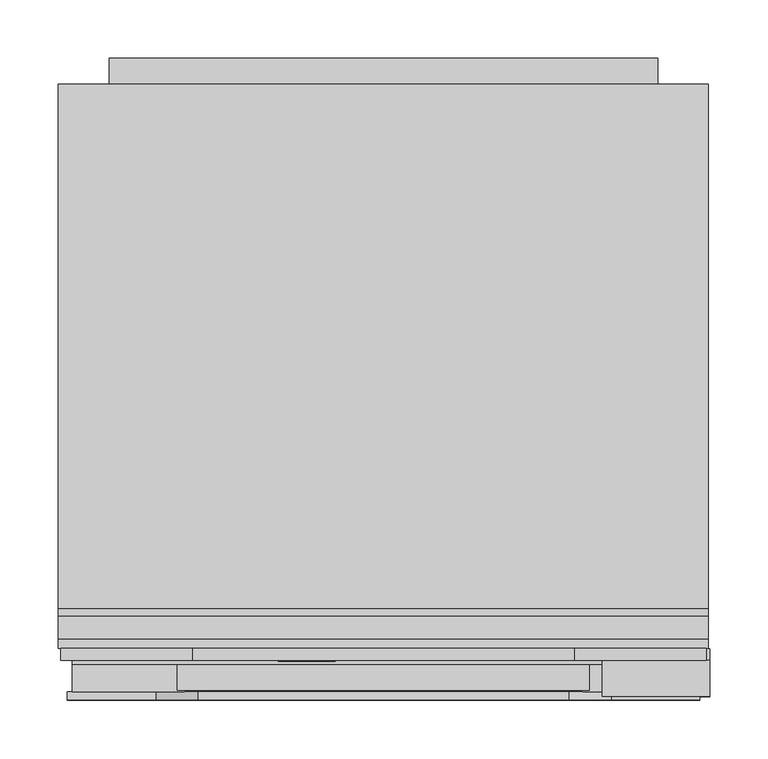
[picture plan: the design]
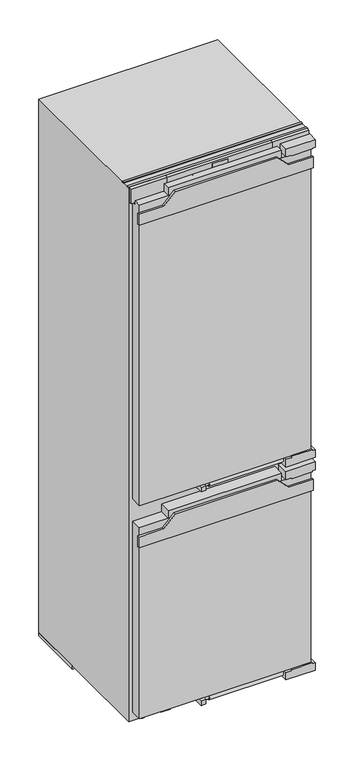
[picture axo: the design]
"""IFC4 building model written with IfcOpenShell, lengths in millimetres: proxy geometry."""

from ifc_helpers import new_model, si_unit, point, frame, frame_2d, origin, origin_with_axes, place, context, project, spatial, polyline, circle_curve, ellipse_curve, trimmed, segment, composite_curve, outline, extrude, faceted_brep, source, transform, mapped, element, save
from ifc_brep_helpers import plane_surface, cylinder_surface, revolved_surface, extruded_surface, advanced_brep


def specialty_equipment_309ff2e4(model_context):
    return source(origin(), model_context, "Body", "SolidModel", [
        advanced_brep(
        [(-46.64, 33.0, 1742.896), (-46.64, 33.0, 1743.704), (-41.288, 33.0, 1743.704), (-50.6, 33.0, 1743.704), (-48.4, 33.0, 1741.0), (-41.424, 33.0, 1742.896), (-43.84, 33.0, 1742.896), (-45.744, 33.0, 1742.0), (-46.64, 33.0, 1744.728), (-46.64, 33.0, 1745.6), (-45.272, 33.0, 1745.6), (-45.272, 33.0, 1744.728), (-46.64, 34.0, 1742.896), (-45.744, 34.0, 1742.0), (-43.84, 34.0, 1742.896), (-41.424, 34.0, 1742.896), (-48.4, 34.0, 1741.0), (-50.6, 34.0, 1743.704), (-41.288, 34.0, 1743.704), (-46.64, 34.0, 1743.704), (-46.64, 34.0, 1744.728), (-45.272, 34.0, 1744.728), (-45.272, 34.0, 1745.6), (-46.64, 34.0, 1745.6)],
        [
            (0, 1),
            (1, 2),
            (2, 3, ellipse_curve(frame((-45.944, 33.0, 1743.704), z_axis=(0.0, -1.0, 0.0), x_axis=(-1.0, 0.0, 0.0)), 4.656, 3.848)),
            (3, 4, circle_curve(frame((-47.5039564, 33.0, 1743.976), z_axis=(0.0, -1.0, 0.0), x_axis=(0.0, 0.0, -1.0)), 3.1079688)),
            (4, 5, circle_curve(frame((-46.0372064, 33.0, 1746.088), z_axis=(0.0, -1.0, 0.0), x_axis=(0.0, 0.0, -1.0)), 5.6098607)),
            (5, 6),
            (6, 7, circle_curve(frame((-45.3529412, 33.0, 1743.64), z_axis=(0.0, 1.0, 0.0), x_axis=(0.0, 0.0, -1.0)), 1.6859795)),
            (7, 0, circle_curve(frame((-45.744, 33.0, 1742.896), z_axis=(0.0, 1.0, 0.0), x_axis=(0.0, 0.0, -1.0)), 0.896)),
            (8, 9),
            (9, 10, circle_curve(frame((-45.956, 33.0, 1745.6), z_axis=(0.0, 1.0, 0.0), x_axis=(0.0, 0.0, -1.0)), 0.684)),
            (10, 11),
            (11, 8),
            (12, 13, circle_curve(frame((-45.744, 34.0, 1742.896), z_axis=(0.0, -1.0, 0.0), x_axis=(0.0, 0.0, -1.0)), 0.896)),
            (13, 14, circle_curve(frame((-45.3529412, 34.0, 1743.64), z_axis=(0.0, -1.0, 0.0), x_axis=(0.0, 0.0, -1.0)), 1.6859795)),
            (14, 15),
            (15, 16, circle_curve(frame((-46.0372064, 34.0, 1746.088), z_axis=(0.0, 1.0, 0.0), x_axis=(0.0, 0.0, -1.0)), 5.6098607)),
            (16, 17, circle_curve(frame((-47.5039564, 34.0, 1743.976), z_axis=(0.0, 1.0, 0.0), x_axis=(0.0, 0.0, -1.0)), 3.1079688)),
            (17, 18, ellipse_curve(frame((-45.944, 34.0, 1743.704), z_axis=(0.0, 1.0, 0.0), x_axis=(-1.0, 0.0, 0.0)), 4.656, 3.848)),
            (18, 19),
            (19, 12),
            (20, 21),
            (21, 22),
            (22, 23, circle_curve(frame((-45.956, 34.0, 1745.6), z_axis=(0.0, -1.0, 0.0), x_axis=(0.0, 0.0, -1.0)), 0.684)),
            (23, 20),
            (0, 12),
            (19, 1),
            (18, 2),
            (5, 15),
            (14, 6),
            (17, 3),
            (13, 7),
            (16, 4),
            (8, 20),
            (23, 9),
            (22, 10),
            (21, 11),
        ],
        [
            plane_surface(frame((-46.64, 33.0, 1743.704), z_axis=(0.0, -1.0, 0.0), x_axis=(0.0, 0.0, 1.0))),
            plane_surface(frame((-46.64, 34.0, 1743.704), z_axis=(0.0, 1.0, 0.0), x_axis=(0.0, 0.0, -1.0))),
            plane_surface(frame((-46.64, 33.0, 1742.896), z_axis=(1.0, 0.0, 0.0), x_axis=(0.0, 1.0, 0.0))),
            plane_surface(frame((-46.64, 33.0, 1743.704), z_axis=(0.0, 0.0, -1.0), x_axis=(0.0, 1.0, 0.0))),
            plane_surface(frame((-41.424, 33.0, 1742.896), z_axis=(0.0, 0.0, 1.0), x_axis=(0.0, 1.0, 0.0))),
            extruded_surface(trimmed(ellipse_curve(frame((-45.944, 35.0, 1743.704), z_axis=(0.0, -1.0, 0.0), x_axis=(-1.0, 0.0, 0.0)), 4.656, 3.848), [point((-41.288, 35.0, 1743.704))], [point((-50.6, 35.0, 1743.704))], True, "CARTESIAN"), (0.0, -1.0, 0.0), 1.0),
            revolved_surface(polyline([(-45.3529412, 34.0, 1741.9540205), (-45.3529412, 33.0, 1741.9540205)]), (-45.3529412, 34.0, 1743.64), (0.0, 1.0, 0.0)),
            revolved_surface(polyline([(-45.744, 34.0, 1742.0), (-45.744, 33.0, 1742.0)]), (-45.744, 34.0, 1742.896), (0.0, 1.0, 0.0)),
            cylinder_surface(frame((-47.5039564, 34.0, 1743.976), z_axis=(0.0, -1.0, 0.0), x_axis=(0.0, 0.0, -1.0)), 3.1079688),
            cylinder_surface(frame((-46.0372064, 34.0, 1746.088), z_axis=(0.0, -1.0, 0.0), x_axis=(0.0, 0.0, -1.0)), 5.6098607),
            plane_surface(frame((-46.64, 33.0, 1744.728), z_axis=(1.0, 0.0, 0.0), x_axis=(0.0, 1.0, 0.0))),
            revolved_surface(polyline([(-45.956, 34.0, 1744.916), (-45.956, 33.0, 1744.916)]), (-45.956, 34.0, 1745.6), (0.0, 1.0, 0.0)),
            plane_surface(frame((-45.272, 33.0, 1745.6), z_axis=(-1.0, 0.0, 0.0), x_axis=(0.0, 1.0, 0.0))),
            plane_surface(frame((-45.272, 33.0, 1744.728), z_axis=(0.0, 0.0, 1.0), x_axis=(0.0, 1.0, 0.0))),
        ],
        [
            (0, [[1, 2, 3, 4, 5, 6, 7, 8], [9, 10, 11, 12]]),
            (1, [[13, 14, 15, 16, 17, 18, 19, 20], [21, 22, 23, 24]]),
            (2, [[-1, 25, -20, 26]]),
            (3, [[-2, -26, -19, 27]]),
            (4, [[-6, 28, -15, 29]]),
            (5, [[-3, -27, -18, 30]]),
            (6, [[-7, -29, -14, 31]]),
            (7, [[-8, -31, -13, -25]]),
            (8, [[-4, -30, -17, 32]]),
            (9, [[-5, -32, -16, -28]]),
            (10, [[-9, 33, -24, 34]]),
            (11, [[-10, -34, -23, 35]]),
            (12, [[-11, -35, -22, 36]]),
            (13, [[-12, -36, -21, -33]]),
        ],
    ),
        advanced_brep(
        [(-63.336, 33.0, 1742.896), (-63.336, 33.0, 1743.704), (-57.984, 33.0, 1743.704), (-67.296, 33.0, 1743.704), (-65.096, 33.0, 1741.0), (-58.12, 33.0, 1742.896), (-60.536, 33.0, 1742.896), (-62.44, 33.0, 1742.0), (-63.336, 33.0, 1744.728), (-63.336, 33.0, 1745.6), (-61.968, 33.0, 1745.6), (-61.968, 33.0, 1744.728), (-63.336, 34.0, 1742.896), (-62.44, 34.0, 1742.0), (-60.536, 34.0, 1742.896), (-58.12, 34.0, 1742.896), (-65.096, 34.0, 1741.0), (-67.296, 34.0, 1743.704), (-57.984, 34.0, 1743.704), (-63.336, 34.0, 1743.704), (-63.336, 34.0, 1744.728), (-61.968, 34.0, 1744.728), (-61.968, 34.0, 1745.6), (-63.336, 34.0, 1745.6)],
        [
            (0, 1),
            (1, 2),
            (2, 3, ellipse_curve(frame((-62.64, 33.0, 1743.704), z_axis=(0.0, -1.0, 0.0), x_axis=(-1.0, 0.0, 0.0)), 4.656, 3.848)),
            (3, 4, circle_curve(frame((-64.1999564, 33.0, 1743.976), z_axis=(0.0, -1.0, 0.0), x_axis=(0.0, 0.0, -1.0)), 3.1079688)),
            (4, 5, circle_curve(frame((-62.7332064, 33.0, 1746.088), z_axis=(0.0, -1.0, 0.0), x_axis=(0.0, 0.0, -1.0)), 5.6098607)),
            (5, 6),
            (6, 7, circle_curve(frame((-62.0489412, 33.0, 1743.64), z_axis=(0.0, 1.0, 0.0), x_axis=(0.0, 0.0, -1.0)), 1.6859795)),
            (7, 0, circle_curve(frame((-62.44, 33.0, 1742.896), z_axis=(0.0, 1.0, 0.0), x_axis=(0.0, 0.0, -1.0)), 0.896)),
            (8, 9),
            (9, 10, circle_curve(frame((-62.652, 33.0, 1745.6), z_axis=(0.0, 1.0, 0.0), x_axis=(0.0, 0.0, -1.0)), 0.684)),
            (10, 11),
            (11, 8),
            (12, 13, circle_curve(frame((-62.44, 34.0, 1742.896), z_axis=(0.0, -1.0, 0.0), x_axis=(0.0, 0.0, -1.0)), 0.896)),
            (13, 14, circle_curve(frame((-62.0489412, 34.0, 1743.64), z_axis=(0.0, -1.0, 0.0), x_axis=(0.0, 0.0, -1.0)), 1.6859795)),
            (14, 15),
            (15, 16, circle_curve(frame((-62.7332064, 34.0, 1746.088), z_axis=(0.0, 1.0, 0.0), x_axis=(0.0, 0.0, -1.0)), 5.6098607)),
            (16, 17, circle_curve(frame((-64.1999564, 34.0, 1743.976), z_axis=(0.0, 1.0, 0.0), x_axis=(0.0, 0.0, -1.0)), 3.1079688)),
            (17, 18, ellipse_curve(frame((-62.64, 34.0, 1743.704), z_axis=(0.0, 1.0, 0.0), x_axis=(-1.0, 0.0, 0.0)), 4.656, 3.848)),
            (18, 19),
            (19, 12),
            (20, 21),
            (21, 22),
            (22, 23, circle_curve(frame((-62.652, 34.0, 1745.6), z_axis=(0.0, -1.0, 0.0), x_axis=(0.0, 0.0, -1.0)), 0.684)),
            (23, 20),
            (0, 12),
            (19, 1),
            (18, 2),
            (5, 15),
            (14, 6),
            (17, 3),
            (13, 7),
            (16, 4),
            (8, 20),
            (23, 9),
            (22, 10),
            (21, 11),
        ],
        [
            plane_surface(frame((-63.336, 33.0, 1743.704), z_axis=(0.0, -1.0, 0.0), x_axis=(0.0, 0.0, 1.0))),
            plane_surface(frame((-63.336, 34.0, 1743.704), z_axis=(0.0, 1.0, 0.0), x_axis=(0.0, 0.0, -1.0))),
            plane_surface(frame((-63.336, 33.0, 1742.896), z_axis=(1.0, 0.0, 0.0), x_axis=(0.0, 1.0, 0.0))),
            plane_surface(frame((-63.336, 33.0, 1743.704), z_axis=(0.0, 0.0, -1.0), x_axis=(0.0, 1.0, 0.0))),
            plane_surface(frame((-58.12, 33.0, 1742.896), z_axis=(0.0, 0.0, 1.0), x_axis=(0.0, 1.0, 0.0))),
            extruded_surface(trimmed(ellipse_curve(frame((-62.64, 35.0, 1743.704), z_axis=(0.0, -1.0, 0.0), x_axis=(-1.0, 0.0, 0.0)), 4.656, 3.848), [point((-57.984, 35.0, 1743.704))], [point((-67.296, 35.0, 1743.704))], True, "CARTESIAN"), (0.0, -1.0, 0.0), 1.0),
            revolved_surface(polyline([(-62.0489412, 34.0, 1741.9540205), (-62.0489412, 33.0, 1741.9540205)]), (-62.0489412, 34.0, 1743.64), (0.0, 1.0, 0.0)),
            revolved_surface(polyline([(-62.44, 34.0, 1742.0), (-62.44, 33.0, 1742.0)]), (-62.44, 34.0, 1742.896), (0.0, 1.0, 0.0)),
            cylinder_surface(frame((-64.1999564, 34.0, 1743.976), z_axis=(0.0, -1.0, 0.0), x_axis=(0.0, 0.0, -1.0)), 3.1079688),
            cylinder_surface(frame((-62.7332064, 34.0, 1746.088), z_axis=(0.0, -1.0, 0.0), x_axis=(0.0, 0.0, -1.0)), 5.6098607),
            plane_surface(frame((-63.336, 33.0, 1744.728), z_axis=(1.0, 0.0, 0.0), x_axis=(0.0, 1.0, 0.0))),
            revolved_surface(polyline([(-62.652, 34.0, 1744.916), (-62.652, 33.0, 1744.916)]), (-62.652, 34.0, 1745.6), (0.0, 1.0, 0.0)),
            plane_surface(frame((-61.968, 33.0, 1745.6), z_axis=(-1.0, 0.0, 0.0), x_axis=(0.0, 1.0, 0.0))),
            plane_surface(frame((-61.968, 33.0, 1744.728), z_axis=(0.0, 0.0, 1.0), x_axis=(0.0, 1.0, 0.0))),
        ],
        [
            (0, [[1, 2, 3, 4, 5, 6, 7, 8], [9, 10, 11, 12]]),
            (1, [[13, 14, 15, 16, 17, 18, 19, 20], [21, 22, 23, 24]]),
            (2, [[-1, 25, -20, 26]]),
            (3, [[-2, -26, -19, 27]]),
            (4, [[-6, 28, -15, 29]]),
            (5, [[-3, -27, -18, 30]]),
            (6, [[-7, -29, -14, 31]]),
            (7, [[-8, -31, -13, -25]]),
            (8, [[-4, -30, -17, 32]]),
            (9, [[-5, -32, -16, -28]]),
            (10, [[-9, 33, -24, 34]]),
            (11, [[-10, -34, -23, 35]]),
            (12, [[-11, -35, -22, 36]]),
            (13, [[-12, -36, -21, -33]]),
        ],
    ),
        extrude(outline(polyline([(1748.528, -72.08), (1747.232, -71.472), (1748.496, -68.76), (1749.792, -69.36), (1748.528, -72.08)])), frame((0.0, 33.0, 0.0), z_axis=(0.0, 1.0, 0.0), x_axis=(0.0, 0.0, 1.0)), (0.0, 0.0, 1.0), 1.0),
        extrude(outline(polyline([(1747.056, -74.056), (1745.624, -74.056), (1745.624, -73.104), (1742.344, -73.104), (1742.344, -74.056), (1741.0, -74.056), (1741.0, -67.744), (1742.344, -67.744), (1742.344, -68.672), (1747.056, -68.672), (1747.056, -74.056)])), frame((0.0, 33.0, 0.0), z_axis=(0.0, 1.0, 0.0), x_axis=(0.0, 0.0, 1.0)), (0.0, 0.0, 1.0), 1.0),
        extrude(outline(polyline([(1747.696, -57.536), (1747.696, -56.576), (1742.344, -56.576), (1742.344, -57.536), (1741.0, -57.536), (1741.0, -51.048), (1742.344, -51.048), (1742.344, -52.032), (1749.0, -52.032), (1749.0, -57.536), (1747.696, -57.536)])), frame((0.0, 33.0, 0.0), z_axis=(0.0, 1.0, 0.0), x_axis=(0.0, 0.0, 1.0)), (0.0, 0.0, 1.0), 1.0),
        extrude(outline(polyline([(1747.696, -90.0), (1747.696, -89.032), (1742.344, -89.032), (1742.344, -90.0), (1741.0, -90.0), (1741.0, -86.48), (1742.344, -86.48), (1742.344, -87.44), (1745.7471247, -87.44), (1741.0, -83.864), (1745.8152223, -80.272), (1742.344, -80.272), (1742.344, -81.256), (1741.0, -81.256), (1741.0, -74.872), (1742.344, -74.872), (1742.344, -75.888), (1747.696, -75.888), (1747.696, -74.872), (1749.0, -74.872), (1749.0, -79.744), (1746.0, -82.08), (1749.0, -84.424), (1749.0, -90.0), (1747.696, -90.0)])), frame((0.0, 33.0, 0.0), z_axis=(0.0, 1.0, 0.0), x_axis=(0.0, 0.0, 1.0)), (0.0, 0.0, 1.0), 1.0),
        extrude(outline(polyline([(607.0, 271.0), (643.0, 271.0), (643.0, 195.0), (679.0, 159.0), (679.0, -159.0), (643.0, -195.0), (643.0, -271.0), (607.0, -271.0), (607.0, 271.0)])), frame((0.0, 0.0, 0.0), z_axis=(0.0, 1.0, 0.0), x_axis=(0.0, 0.0, 1.0)), (0.0, 0.0, 1.0), 7.0),
        extrude(outline(polyline([(1669.0, 271.0), (1705.0, 271.0), (1705.0, 195.0), (1741.0, 159.0), (1741.0, -159.0), (1705.0, -195.0), (1705.0, -271.0), (1669.0, -271.0), (1669.0, 271.0)])), frame((0.0, 0.0, 0.0), z_axis=(0.0, 1.0, 0.0), x_axis=(0.0, 0.0, 1.0)), (0.0, 0.0, 1.0), 7.0),
        extrude(outline(composite_curve([segment(trimmed(circle_curve(frame_2d((-65.5, 25.0)), 6.5), [point((-72.0, 25.0))], [point((-59.0, 25.0))], False, "CARTESIAN"), True, "CONTINUOUS"), segment(trimmed(circle_curve(frame_2d((-65.5, 25.0)), 6.5), [point((-59.0, 25.0))], [point((-72.0, 25.0))], False, "CARTESIAN"), True, "CONTINUOUS")], self_intersect=False)), frame((0.0, 0.0, 732.0), z_axis=(0.0, 0.0, 1.0), x_axis=(1.0, 0.0, 0.0)), (0.0, 0.0, 1.0), 8.0),
        extrude(outline(polyline([(-74.0, 42.0), (-59.0, 42.0), (-59.0, 8.0), (-74.0, 8.0), (-74.0, 42.0)])), frame((0.0, 0.0, 717.3963013), z_axis=(0.0, 0.0, 1.0), x_axis=(1.0, 0.0, 0.0)), (0.0, 0.0, 1.0), 14.6036987),
        extrude(outline(composite_curve([segment(trimmed(circle_curve(frame_2d((-65.5, 25.0)), 6.5), [point((-72.0, 25.0))], [point((-59.0, 25.0))], False, "CARTESIAN"), True, "CONTINUOUS"), segment(trimmed(circle_curve(frame_2d((-65.5, 25.0)), 6.5), [point((-59.0, 25.0))], [point((-72.0, 25.0))], False, "CARTESIAN"), True, "CONTINUOUS")], self_intersect=False)), frame((0.0, 0.0, 29.0), z_axis=(0.0, 0.0, 1.0), x_axis=(1.0, 0.0, 0.0)), (0.0, 0.0, 1.0), 9.0),
        extrude(outline(polyline([(-74.0, 42.0), (-59.0, 42.0), (-59.0, 8.0), (-74.0, 8.0), (-74.0, 42.0)])), frame((0.0, 0.0, 14.3963013), z_axis=(0.0, 0.0, 1.0), x_axis=(1.0, 0.0, 0.0)), (0.0, 0.0, 1.0), 14.6036987),
        extrude(outline(polyline([(736.0, 205.5), (736.0, 187.5), (711.0, 187.5), (711.0, 279.5), (736.0, 279.5), (736.0, 269.5), (740.0, 269.5), (740.0, 205.5), (736.0, 205.5)])), frame((0.0, 3.0, 0.0), z_axis=(0.0, 1.0, 0.0), x_axis=(0.0, 0.0, 1.0)), (0.0, 0.0, 1.0), 41.0),
        extrude(outline(polyline([(176.5, 8.0), (-176.5, 8.0), (-176.5, 30.0), (176.5, 30.0), (176.5, 8.0)])), frame((0.0, 0.0, 1730.0), z_axis=(0.0, 0.0, 1.0), x_axis=(1.0, 0.0, 0.0)), (0.0, 0.0, 1.0), 25.0),
        extrude(outline(polyline([(7.0, 740.0), (7.0, 1730.0), (30.0, 1730.0), (30.0, 1715.0), (44.0, 1715.0), (44.0, 740.0), (7.0, 740.0)])), frame((-266.5, 0.0, 0.0), z_axis=(1.0, 0.0, 0.0), x_axis=(0.0, 1.0, 0.0)), (0.0, 0.0, 1.0), 533.0),
        extrude(outline(polyline([(-176.5, 44.0), (176.5, 44.0), (176.5, 8.0), (-176.5, 8.0), (-176.5, 44.0)])), frame((0.0, 0.0, 667.0), z_axis=(0.0, 0.0, 1.0), x_axis=(1.0, 0.0, 0.0)), (0.0, 0.0, 1.0), 25.0),
        extrude(outline(polyline([(696.0, 279.5), (696.0, 187.5), (670.0, 187.5), (670.0, 205.5), (667.0, 205.5), (667.0, 269.5), (670.0, 269.5), (670.0, 279.5), (696.0, 279.5)])), frame((0.0, 3.0, 0.0), z_axis=(0.0, 1.0, 0.0), x_axis=(0.0, 0.0, 1.0)), (0.0, 0.0, 1.0), 41.0),
        extrude(outline(polyline([(34.0, 205.5), (34.0, 187.5), (10.0, 187.5), (10.0, 279.5), (34.0, 279.5), (34.0, 269.5), (38.0, 269.5), (38.0, 205.5), (34.0, 205.5)])), frame((0.0, 3.0, 0.0), z_axis=(0.0, 1.0, 0.0), x_axis=(0.0, 0.0, 1.0)), (0.0, 0.0, 1.0), 41.0),
        extrude(outline(polyline([(1732.0, 269.5), (1732.0, 279.5), (1757.0, 279.5), (1757.0, 187.5), (1732.0, 187.5), (1732.0, 205.5), (1730.0, 205.5), (1730.0, 269.5), (1732.0, 269.5)])), frame((0.0, 3.0, 0.0), z_axis=(0.0, 1.0, 0.0), x_axis=(0.0, 0.0, 1.0)), (0.0, 0.0, 1.0), 31.0),
        extrude(outline(polyline([(-266.5, 44.0), (266.5, 44.0), (266.5, 7.0), (-266.5, 7.0), (-266.5, 44.0)])), frame((0.0, 0.0, 38.0), z_axis=(0.0, 0.0, 1.0), x_axis=(1.0, 0.0, 0.0)), (0.0, 0.0, 1.0), 629.0),
        extrude(outline(composite_curve([segment(trimmed(circle_curve(frame_2d((25.0, 726.0)), 6.0), [point((25.0, 720.0))], [point((25.0, 732.0))], False, "CARTESIAN"), True, "CONTINUOUS"), segment(trimmed(circle_curve(frame_2d((25.0, 726.0)), 6.0), [point((25.0, 732.0))], [point((25.0, 720.0))], False, "CARTESIAN"), True, "CONTINUOUS")], self_intersect=False)), frame((-59.0, 0.0, 0.0), z_axis=(1.0, 0.0, 0.0), x_axis=(0.0, 1.0, 0.0)), (0.0, 0.0, 1.0), 16.0),
        extrude(outline(composite_curve([segment(trimmed(circle_curve(frame_2d((25.0, 726.0)), 9.0), [point((25.0, 717.0))], [point((25.0, 735.0))], False, "CARTESIAN"), True, "CONTINUOUS"), segment(trimmed(circle_curve(frame_2d((25.0, 726.0)), 9.0), [point((25.0, 735.0))], [point((25.0, 717.0))], False, "CARTESIAN"), True, "CONTINUOUS")], self_intersect=False)), frame((-43.0, 0.0, 0.0), z_axis=(1.0, 0.0, 0.0), x_axis=(0.0, 1.0, 0.0)), (0.0, 0.0, 1.0), 230.5),
        extrude(outline(composite_curve([segment(trimmed(circle_curve(frame_2d((25.0, 23.0)), 9.0), [point((25.0, 14.0))], [point((25.0, 32.0))], False, "CARTESIAN"), True, "CONTINUOUS"), segment(trimmed(circle_curve(frame_2d((25.0, 23.0)), 9.0), [point((25.0, 32.0))], [point((25.0, 14.0))], False, "CARTESIAN"), True, "CONTINUOUS")], self_intersect=False)), frame((-43.0, 0.0, 0.0), z_axis=(1.0, 0.0, 0.0), x_axis=(0.0, 1.0, 0.0)), (0.0, 0.0, 1.0), 230.5),
        extrude(outline(composite_curve([segment(trimmed(circle_curve(frame_2d((25.0, 23.0)), 6.0), [point((25.0, 17.0))], [point((25.0, 29.0))], False, "CARTESIAN"), True, "CONTINUOUS"), segment(trimmed(circle_curve(frame_2d((25.0, 23.0)), 6.0), [point((25.0, 29.0))], [point((25.0, 17.0))], False, "CARTESIAN"), True, "CONTINUOUS")], self_intersect=False)), frame((-59.0, 0.0, 0.0), z_axis=(1.0, 0.0, 0.0), x_axis=(0.0, 1.0, 0.0)), (0.0, 0.0, 1.0), 16.0),
        faceted_brep([(163.5, 34.0, 1770.0), (-163.5, 34.0, 1770.0), (-163.5, 34.0, 1721.0), (163.5, 34.0, 1721.0), (24.5, 34.0, 1765.0), (24.5, 34.0, 1727.0), (-24.5, 34.0, 1727.0), (-24.5, 34.0, 1765.0), (163.5, 44.0, 1770.0), (163.5, 44.0, 1721.0), (-163.5, 44.0, 1721.0), (-163.5, 44.0, 1770.0), (24.5, 35.0, 1765.0), (-24.5, 35.0, 1765.0), (-24.5, 35.0, 1727.0), (24.5, 35.0, 1727.0)], [[[0, 1, 2, 3], [4, 5, 6, 7]], [[8, 9, 10, 11]], [[0, 3, 9, 8]], [[3, 2, 10, 9]], [[2, 1, 11, 10]], [[1, 0, 8, 11]], [[12, 13, 14, 15]], [[12, 15, 5, 4]], [[15, 14, 6, 5]], [[14, 13, 7, 6]], [[13, 12, 4, 7]]]),
        extrude(outline(polyline([(163.5, 44.0), (276.5, 44.0), (276.5, 34.0), (163.5, 34.0), (163.5, 44.0)])), frame((0.0, 0.0, 1721.0), z_axis=(0.0, 0.0, 1.0), x_axis=(1.0, 0.0, 0.0)), (0.0, 0.0, 1.0), 49.0),
        extrude(outline(polyline([(-276.5, 44.0), (-163.5, 44.0), (-163.5, 34.0), (-276.5, 34.0), (-276.5, 44.0)])), frame((0.0, 0.0, 1721.0), z_axis=(0.0, 0.0, 1.0), x_axis=(1.0, 0.0, 0.0)), (0.0, 0.0, 1.0), 49.0),
        extrude(outline(polyline([(-24.5, 35.0), (24.5, 35.0), (24.5, 34.0), (-24.5, 34.0), (-24.5, 35.0)])), frame((0.0, 0.0, 1727.0), z_axis=(0.0, 0.0, 1.0), x_axis=(1.0, 0.0, 0.0)), (0.0, 0.0, 1.0), 38.0),
        extrude(outline(polyline([(1647.0, -235.0), (27.0, -235.0), (27.0, 235.0), (130.0, 235.0), (130.0, 180.0), (160.0, 180.0), (160.0, 235.0), (1647.0, 235.0), (1647.0, -235.0)])), frame((0.0, 528.0, 0.0), z_axis=(0.0, 1.0, 0.0), x_axis=(0.0, 0.0, 1.0)), (0.0, 0.0, 1.0), 22.0),
        extrude(outline(polyline([(-144.929185, 52.0), (-174.0, 52.0), (-194.6983363, 348.0), (-165.6275213, 348.0), (-144.929185, 52.0)])), origin_with_axes(), (0.0, 0.0, 1.0), 10.0),
        extrude(outline(polyline([(144.929185, 52.0), (165.6275213, 348.0), (194.6983363, 348.0), (174.0, 52.0), (144.929185, 52.0)])), origin_with_axes(), (0.0, 0.0, 1.0), 10.0),
        extrude(outline(polyline([(541.4384039, 149.874164), (548.6647626, 149.874164), (548.6647626, 139.824714), (541.2826236, 139.824714), (541.2826236, 141.0836119), (547.4056247, 141.0836119), (547.4056247, 144.3750411), (541.7614845, 144.3750411), (541.7614845, 145.6249589), (547.4056247, 145.6249589), (547.4056247, 148.6148402), (541.4384039, 148.6148402), (541.4384039, 149.874164)])), frame((193.5, 0.0, 0.0), z_axis=(1.0, 0.0, 0.0), x_axis=(0.0, 1.0, 0.0)), (0.0, 0.0, 1.0), 1.0),
        extrude(outline(polyline([(538.1383052, 149.8716162), (539.399354, 149.8716162), (539.399354, 139.824714), (533.1225656, 139.824714), (533.1225656, 141.0927041), (538.1383052, 141.0927041), (538.1383052, 149.8716162)])), frame((193.5, 0.0, 0.0), z_axis=(1.0, 0.0, 0.0), x_axis=(0.0, 1.0, 0.0)), (0.0, 0.0, 1.0), 1.0),
        advanced_brep(
        [(232.0, 528.0, 145.0), (217.0, 528.0, 145.0), (232.0, 549.5, 145.0), (217.0, 534.5, 145.0), (194.5, 549.5, 145.0), (194.5, 534.5, 145.0)],
        [
            (0, 1, circle_curve(frame((224.5, 528.0, 145.0), z_axis=(0.0, -1.0, 0.0), x_axis=(-1.0, 0.0, 0.0)), 7.5)),
            (1, 0, circle_curve(frame((224.5, 528.0, 145.0), z_axis=(0.0, -1.0, 0.0), x_axis=(-1.0, 0.0, 0.0)), 7.5)),
            (0, 2),
            (2, 3, ellipse_curve(frame((224.5, 542.0, 145.0), z_axis=(0.7071067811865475, -0.7071067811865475, 0.0), x_axis=(-0.7071067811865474, -0.7071067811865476, 0.0)), 10.6066017, 7.5)),
            (3, 1),
            (3, 2, ellipse_curve(frame((224.5, 542.0, 145.0), z_axis=(0.7071067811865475, -0.7071067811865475, 0.0), x_axis=(-0.7071067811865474, -0.7071067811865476, 0.0)), 10.6066017, 7.5)),
            (4, 5, circle_curve(frame((194.5, 542.0, 145.0), z_axis=(-1.0, 0.0, 0.0), x_axis=(0.0, -1.0, 0.0)), 7.5)),
            (5, 4, circle_curve(frame((194.5, 542.0, 145.0), z_axis=(-1.0, 0.0, 0.0), x_axis=(0.0, -1.0, 0.0)), 7.5)),
            (2, 4),
            (5, 3),
        ],
        [
            plane_surface(frame((224.5, 528.0, 145.0), z_axis=(0.0, -1.0, 0.0), x_axis=(0.0, 0.0, 1.0))),
            cylinder_surface(frame((224.5, 528.0, 145.0), z_axis=(0.0, -1.0, 0.0), x_axis=(-1.0, 0.0, 0.0)), 7.5),
            plane_surface(frame((194.5, 542.0, 145.0), z_axis=(-1.0, 0.0, 0.0), x_axis=(0.0, 0.0, 1.0))),
            cylinder_surface(frame((224.5, 542.0, 145.0), z_axis=(1.0, 0.0, 0.0), x_axis=(0.0, -1.0, 0.0)), 7.5),
        ],
        [
            (0, [[1, 2]]),
            (1, [[-1, 3, 4, 5]]),
            (1, [[-2, -5, 6, -3]]),
            (2, [[7, 8]]),
            (3, [[-4, 9, -8, 10]]),
            (3, [[-6, -10, -7, -9]]),
        ],
    ),
        extrude(outline(polyline([(-34.0, 44.0), (34.0, 44.0), (34.0, 35.0), (-34.0, 35.0), (-34.0, 44.0)])), frame((0.0, 0.0, 13.0), z_axis=(0.0, 0.0, 1.0), x_axis=(1.0, 0.0, 0.0)), (0.0, 0.0, 1.0), 19.0),
        extrude(outline(polyline([(278.5, 52.0), (278.5, 44.0), (-278.5, 44.0), (-278.5, 52.0), (278.5, 52.0)])), frame((0.0, 0.0, 1767.0), z_axis=(0.0, 0.0, 1.0), x_axis=(1.0, 0.0, 0.0)), (0.0, 0.0, 1.0), 3.0),
        extrude(outline(polyline([(278.5, 78.0), (278.5, 72.0), (-278.5, 72.0), (-278.5, 78.0), (278.5, 78.0)])), frame((0.0, 0.0, 1767.0), z_axis=(0.0, 0.0, 1.0), x_axis=(1.0, 0.0, 0.0)), (0.0, 0.0, 1.0), 3.0),
        extrude(outline(polyline([(-242.5, 44.0), (-242.5, 490.0), (242.5, 490.0), (242.5, 44.0), (-242.5, 44.0)])), frame((0.0, 0.0, 960.0), z_axis=(0.0, 0.0, 1.0), x_axis=(1.0, 0.0, 0.0)), (0.0, 0.0, 1.0), 3.0),
        extrude(outline(polyline([(-217.5, 312.0), (-217.5, 451.0), (217.5, 451.0), (217.5, 312.0), (-217.5, 312.0)])), frame((0.0, 0.0, 93.0), z_axis=(0.0, 0.0, 1.0), x_axis=(1.0, 0.0, 0.0)), (0.0, 0.0, 1.0), 181.0),
        extrude(outline(composite_curve([segment(trimmed(circle_curve(frame_2d((228.0, 64.0)), 11.0), [point((239.0, 64.0))], [point((217.0, 64.0))], False, "CARTESIAN"), True, "CONTINUOUS"), segment(trimmed(circle_curve(frame_2d((228.0, 64.0)), 11.0), [point((217.0, 64.0))], [point((239.0, 64.0))], False, "CARTESIAN"), True, "CONTINUOUS")], self_intersect=False)), origin_with_axes(), (0.0, 0.0, 1.0), 10.0),
        extrude(outline(composite_curve([segment(trimmed(circle_curve(frame_2d((-228.0, 64.0)), 11.0), [point((-217.0, 64.0))], [point((-239.0, 64.0))], False, "CARTESIAN"), True, "CONTINUOUS"), segment(trimmed(circle_curve(frame_2d((-228.0, 64.0)), 11.0), [point((-239.0, 64.0))], [point((-217.0, 64.0))], False, "CARTESIAN"), True, "CONTINUOUS")], self_intersect=False)), origin_with_axes(), (0.0, 0.0, 1.0), 10.0),
        extrude(outline(polyline([(278.5, 528.0), (278.5, 348.0), (-278.5, 348.0), (-278.5, 528.0), (278.5, 528.0)])), origin_with_axes(), (0.0, 0.0, 1.0), 10.0),
        faceted_brep([(278.5, 528.0, 1767.0), (-278.5, 528.0, 1767.0), (-278.5, 44.0, 1767.0), (278.5, 44.0, 1767.0), (278.5, 528.0, 10.0), (278.5, 44.0, 10.0), (-278.5, 44.0, 10.0), (-278.5, 528.0, 10.0), (242.5, 44.0, 1692.0), (242.5, 44.0, 765.0), (-242.5, 44.0, 765.0), (-242.5, 44.0, 1692.0), (217.5, 44.0, 633.0), (217.5, 44.0, 93.0), (-217.5, 44.0, 93.0), (-217.5, 44.0, 633.0), (242.5, 490.0, 1692.0), (-242.5, 490.0, 1692.0), (-242.5, 490.0, 765.0), (242.5, 490.0, 765.0), (217.5, 451.0, 633.0), (217.5, 451.0, 93.0), (-217.5, 451.0, 633.0), (-217.5, 451.0, 93.0)], [[[0, 1, 2, 3]], [[4, 5, 6, 7]], [[1, 0, 4, 7]], [[2, 1, 7, 6]], [[3, 2, 6, 5], [8, 9, 10, 11], [12, 13, 14, 15]], [[0, 3, 5, 4]], [[16, 17, 18, 19]], [[16, 19, 9, 8]], [[19, 18, 10, 9]], [[18, 17, 11, 10]], [[17, 16, 8, 11]], [[20, 21, 13, 12]], [[22, 15, 14, 23]], [[21, 20, 22, 23]], [[13, 21, 23, 14]], [[20, 12, 15, 22]]]),
    ])


if __name__ == "__main__":
    model = new_model("IFC4")
    model_context = context("Model", 3, world=origin())
    ifc_project = project(units=[si_unit("LENGTHUNIT", "METRE", prefix="MILLI")], contexts=[model_context])
    site = spatial("IfcSite", under=ifc_project)
    building = spatial("IfcBuilding", under=site)
    placement = place(None, origin())
    specialty_equipment_shape = specialty_equipment_309ff2e4(model_context)
    element("IfcBuildingElementProxy", 1, Name="Specialty Equipment", at=placement, inside=building, context=model_context, shape_type="MappedRepresentation", body=[
        mapped(specialty_equipment_shape, transform((0.0, 0.0, 0.0), x_axis=(1.0, 0.0, 0.0), y_axis=(0.0, 1.0, 0.0), z_axis=(0.0, 0.0, 1.0))),
    ])
    save(model, "model.ifc")
